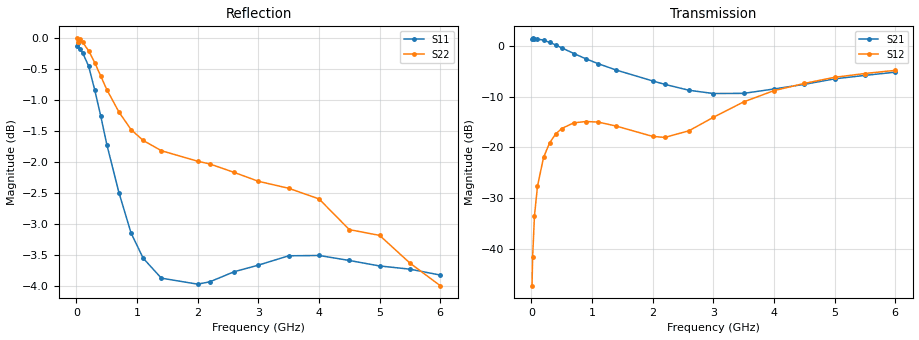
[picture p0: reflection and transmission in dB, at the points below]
! Infineon Technologies  Discrete & RF Semiconductors
! BFS17W
! Si NPN RF Bipolar Junction Transistor in SOT323
! VCE = 3.5 V  IC = 0.3 mA
! Common Emitter S-Parameters:  August  1999
# GHz  S  MA  R  50
!  f  S11  S21  S12  S22
! GHz  MAG  ANG  MAG  ANG  MAG  ANG  MAG  ANG
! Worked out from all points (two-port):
!   36 points, 10 MHz to 6 GHz, reference 50 ohm
!   highest |S21| = 1.55 dB at 20 MHz (marker M1); lowest = -9.3 dB at 3 GHz (marker M2)
!   |S21| within 3 dB of the highest: start of sweep to 700.6 MHz
!   lowest |S11| = -4.0 dB at 2 GHz (marker M3), VSWR 4.45, Z = 11.3 + j2.78 ohm
!   |S11| at or under -10 dB: nowhere
!   |S22| runs from -4.0 to 0.0 dB; largest |S21 - S12| = 1.2
!   S11 on the Smith chart (normalised r, x): 10 MHz: 30, -56; 300 MHz: 0.27, -2.14; 700 MHz: 0.24, -0.80; 1.4 GHz: 0.23, -0.20; 3 GHz: 0.24, +0.38; 6 GHz: 0.51, +1.10
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0.01  0.9854 -1.6  1.189 179.4  0.0043 89.0  0.9999 0.0
0.02  0.9912 -3.7  1.196 177.2  0.0082 91.5  0.9933 -1.0
0.05  0.98 -8.6  1.192 172.6  0.0209 86.8  0.9978 -2.4
0.1  0.9738 -16.8  1.177 165.7  0.0413 79.6  0.9929 -4.9
0.2  0.9496 -33.7  1.149 151.0  0.0796 69.5  0.9772 -9.5
0.3  0.9087 -49.5  1.091 137.8  0.1109 59.9  0.9559 -13.7
0.4  0.8654 -64.0  1.03 125.3  0.1356 51.3  0.9322 -17.5
0.5  0.8207 -77.3  0.964 114.4  0.1537 44.4  0.909 -20.7
0.7  0.7504 -100.5  0.847 95.7  0.1752 33.4  0.8718 -26.5
0.9  0.6961 -119.8  0.75 80.9  0.1803 25.3  0.8438 -31.9
1.1  0.6642 -135.9  0.673 68.5  0.178 19.9  0.8269 -37.3
1.4  0.64 -155.9  0.581 54.4  0.1625 15.9  0.8113 -45.4
2  0.6329 173.3  0.454 36.4  0.1285 26.6  0.7955 -63.2
2.2  0.6357 165.0  0.42 33.1  0.1255 36.0  0.7915 -69.3
2.6  0.6477 149.7  0.367 30.2  0.1462 54.7  0.7792 -82.0
3  0.6557 136.0  0.341 32.1  0.1982 63.8  0.7664 -94.2
3.5  0.6672 121.2  0.342 37.0  0.2817 64.0  0.7565 -110.2
4  0.6676 108.8  0.378 39.4  0.3641 58.3  0.7417 -127.2
4.5  0.6614 98.3  0.42 38.5  0.4288 51.1  0.7005 -142.7
5  0.6547 90.2  0.476 35.4  0.4928 43.9  0.693 -156.3
5.5  0.6508 83.3  0.515 31.1  0.5375 36.9  0.6582 -170.2
6  0.6437 77.9  0.554 26.2  0.5774 30.5  0.6311 177.7
